# Generated by FakeRAM 2.0
VERSION 5.7 ;
BUSBITCHARS "[]" ;
PROPERTYDEFINITIONS
  MACRO width INTEGER ;
  MACRO depth INTEGER ;
  MACRO banks INTEGER ;
END PROPERTYDEFINITIONS
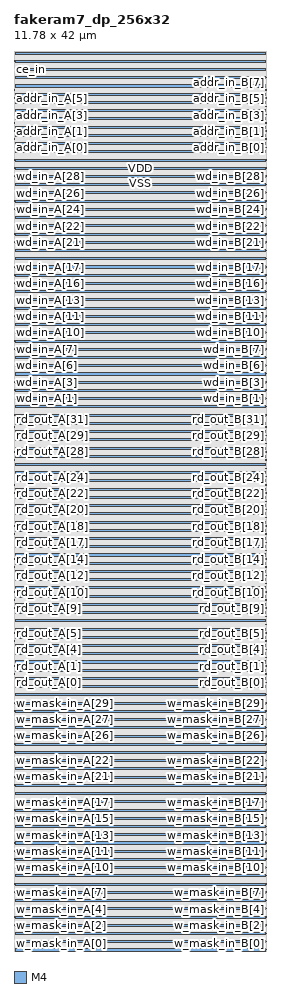
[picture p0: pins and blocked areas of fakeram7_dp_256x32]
MACRO fakeram7_dp_256x32
  PROPERTY width 32 ;
  PROPERTY depth 256 ;
  PROPERTY banks 2 ;
  FOREIGN fakeram7_dp_256x32 0 0 ;
  SYMMETRY X Y ;
  SIZE 11.780 BY 42.000 ;
  CLASS BLOCK ;
  PIN w_mask_in_A[0]
    DIRECTION INPUT ;
    USE SIGNAL ;
    SHAPE ABUTMENT ;
    PORT
      LAYER M4 ;
      RECT 0.000 0.048 0.024 0.072 ;
    END
  END w_mask_in_A[0]
  PIN w_mask_in_B[0]
    DIRECTION INPUT ;
    USE SIGNAL ;
    SHAPE ABUTMENT ;
    PORT
      LAYER M4 ;
      RECT 11.756 0.048 11.780 0.072 ;
    END
  END w_mask_in_B[0]
  PIN w_mask_in_A[1]
    DIRECTION INPUT ;
    USE SIGNAL ;
    SHAPE ABUTMENT ;
    PORT
      LAYER M4 ;
      RECT 0.000 0.432 0.024 0.456 ;
    END
  END w_mask_in_A[1]
  PIN w_mask_in_B[1]
    DIRECTION INPUT ;
    USE SIGNAL ;
    SHAPE ABUTMENT ;
    PORT
      LAYER M4 ;
      RECT 11.756 0.432 11.780 0.456 ;
    END
  END w_mask_in_B[1]
  PIN w_mask_in_A[2]
    DIRECTION INPUT ;
    USE SIGNAL ;
    SHAPE ABUTMENT ;
    PORT
      LAYER M4 ;
      RECT 0.000 0.816 0.024 0.840 ;
    END
  END w_mask_in_A[2]
  PIN w_mask_in_B[2]
    DIRECTION INPUT ;
    USE SIGNAL ;
    SHAPE ABUTMENT ;
    PORT
      LAYER M4 ;
      RECT 11.756 0.816 11.780 0.840 ;
    END
  END w_mask_in_B[2]
  PIN w_mask_in_A[3]
    DIRECTION INPUT ;
    USE SIGNAL ;
    SHAPE ABUTMENT ;
    PORT
      LAYER M4 ;
      RECT 0.000 1.200 0.024 1.224 ;
    END
  END w_mask_in_A[3]
  PIN w_mask_in_B[3]
    DIRECTION INPUT ;
    USE SIGNAL ;
    SHAPE ABUTMENT ;
    PORT
      LAYER M4 ;
      RECT 11.756 1.200 11.780 1.224 ;
    END
  END w_mask_in_B[3]
  PIN w_mask_in_A[4]
    DIRECTION INPUT ;
    USE SIGNAL ;
    SHAPE ABUTMENT ;
    PORT
      LAYER M4 ;
      RECT 0.000 1.584 0.024 1.608 ;
    END
  END w_mask_in_A[4]
  PIN w_mask_in_B[4]
    DIRECTION INPUT ;
    USE SIGNAL ;
    SHAPE ABUTMENT ;
    PORT
      LAYER M4 ;
      RECT 11.756 1.584 11.780 1.608 ;
    END
  END w_mask_in_B[4]
  PIN w_mask_in_A[5]
    DIRECTION INPUT ;
    USE SIGNAL ;
    SHAPE ABUTMENT ;
    PORT
      LAYER M4 ;
      RECT 0.000 1.968 0.024 1.992 ;
    END
  END w_mask_in_A[5]
  PIN w_mask_in_B[5]
    DIRECTION INPUT ;
    USE SIGNAL ;
    SHAPE ABUTMENT ;
    PORT
      LAYER M4 ;
      RECT 11.756 1.968 11.780 1.992 ;
    END
  END w_mask_in_B[5]
  PIN w_mask_in_A[6]
    DIRECTION INPUT ;
    USE SIGNAL ;
    SHAPE ABUTMENT ;
    PORT
      LAYER M4 ;
      RECT 0.000 2.352 0.024 2.376 ;
    END
  END w_mask_in_A[6]
  PIN w_mask_in_B[6]
    DIRECTION INPUT ;
    USE SIGNAL ;
    SHAPE ABUTMENT ;
    PORT
      LAYER M4 ;
      RECT 11.756 2.352 11.780 2.376 ;
    END
  END w_mask_in_B[6]
  PIN w_mask_in_A[7]
    DIRECTION INPUT ;
    USE SIGNAL ;
    SHAPE ABUTMENT ;
    PORT
      LAYER M4 ;
      RECT 0.000 2.736 0.024 2.760 ;
    END
  END w_mask_in_A[7]
  PIN w_mask_in_B[7]
    DIRECTION INPUT ;
    USE SIGNAL ;
    SHAPE ABUTMENT ;
    PORT
      LAYER M4 ;
      RECT 11.756 2.736 11.780 2.760 ;
    END
  END w_mask_in_B[7]
  PIN w_mask_in_A[8]
    DIRECTION INPUT ;
    USE SIGNAL ;
    SHAPE ABUTMENT ;
    PORT
      LAYER M4 ;
      RECT 0.000 3.120 0.024 3.144 ;
    END
  END w_mask_in_A[8]
  PIN w_mask_in_B[8]
    DIRECTION INPUT ;
    USE SIGNAL ;
    SHAPE ABUTMENT ;
    PORT
      LAYER M4 ;
      RECT 11.756 3.120 11.780 3.144 ;
    END
  END w_mask_in_B[8]
  PIN w_mask_in_A[9]
    DIRECTION INPUT ;
    USE SIGNAL ;
    SHAPE ABUTMENT ;
    PORT
      LAYER M4 ;
      RECT 0.000 3.504 0.024 3.528 ;
    END
  END w_mask_in_A[9]
  PIN w_mask_in_B[9]
    DIRECTION INPUT ;
    USE SIGNAL ;
    SHAPE ABUTMENT ;
    PORT
      LAYER M4 ;
      RECT 11.756 3.504 11.780 3.528 ;
    END
  END w_mask_in_B[9]
  PIN w_mask_in_A[10]
    DIRECTION INPUT ;
    USE SIGNAL ;
    SHAPE ABUTMENT ;
    PORT
      LAYER M4 ;
      RECT 0.000 3.888 0.024 3.912 ;
    END
  END w_mask_in_A[10]
  PIN w_mask_in_B[10]
    DIRECTION INPUT ;
    USE SIGNAL ;
    SHAPE ABUTMENT ;
    PORT
      LAYER M4 ;
      RECT 11.756 3.888 11.780 3.912 ;
    END
  END w_mask_in_B[10]
  PIN w_mask_in_A[11]
    DIRECTION INPUT ;
    USE SIGNAL ;
    SHAPE ABUTMENT ;
    PORT
      LAYER M4 ;
      RECT 0.000 4.272 0.024 4.296 ;
    END
  END w_mask_in_A[11]
  PIN w_mask_in_B[11]
    DIRECTION INPUT ;
    USE SIGNAL ;
    SHAPE ABUTMENT ;
    PORT
      LAYER M4 ;
      RECT 11.756 4.272 11.780 4.296 ;
    END
  END w_mask_in_B[11]
  PIN w_mask_in_A[12]
    DIRECTION INPUT ;
    USE SIGNAL ;
    SHAPE ABUTMENT ;
    PORT
      LAYER M4 ;
      RECT 0.000 4.656 0.024 4.680 ;
    END
  END w_mask_in_A[12]
  PIN w_mask_in_B[12]
    DIRECTION INPUT ;
    USE SIGNAL ;
    SHAPE ABUTMENT ;
    PORT
      LAYER M4 ;
      RECT 11.756 4.656 11.780 4.680 ;
    END
  END w_mask_in_B[12]
  PIN w_mask_in_A[13]
    DIRECTION INPUT ;
    USE SIGNAL ;
    SHAPE ABUTMENT ;
    PORT
      LAYER M4 ;
      RECT 0.000 5.040 0.024 5.064 ;
    END
  END w_mask_in_A[13]
  PIN w_mask_in_B[13]
    DIRECTION INPUT ;
    USE SIGNAL ;
    SHAPE ABUTMENT ;
    PORT
      LAYER M4 ;
      RECT 11.756 5.040 11.780 5.064 ;
    END
  END w_mask_in_B[13]
  PIN w_mask_in_A[14]
    DIRECTION INPUT ;
    USE SIGNAL ;
    SHAPE ABUTMENT ;
    PORT
      LAYER M4 ;
      RECT 0.000 5.424 0.024 5.448 ;
    END
  END w_mask_in_A[14]
  PIN w_mask_in_B[14]
    DIRECTION INPUT ;
    USE SIGNAL ;
    SHAPE ABUTMENT ;
    PORT
      LAYER M4 ;
      RECT 11.756 5.424 11.780 5.448 ;
    END
  END w_mask_in_B[14]
  PIN w_mask_in_A[15]
    DIRECTION INPUT ;
    USE SIGNAL ;
    SHAPE ABUTMENT ;
    PORT
      LAYER M4 ;
      RECT 0.000 5.808 0.024 5.832 ;
    END
  END w_mask_in_A[15]
  PIN w_mask_in_B[15]
    DIRECTION INPUT ;
    USE SIGNAL ;
    SHAPE ABUTMENT ;
    PORT
      LAYER M4 ;
      RECT 11.756 5.808 11.780 5.832 ;
    END
  END w_mask_in_B[15]
  PIN w_mask_in_A[16]
    DIRECTION INPUT ;
    USE SIGNAL ;
    SHAPE ABUTMENT ;
    PORT
      LAYER M4 ;
      RECT 0.000 6.192 0.024 6.216 ;
    END
  END w_mask_in_A[16]
  PIN w_mask_in_B[16]
    DIRECTION INPUT ;
    USE SIGNAL ;
    SHAPE ABUTMENT ;
    PORT
      LAYER M4 ;
      RECT 11.756 6.192 11.780 6.216 ;
    END
  END w_mask_in_B[16]
  PIN w_mask_in_A[17]
    DIRECTION INPUT ;
    USE SIGNAL ;
    SHAPE ABUTMENT ;
    PORT
      LAYER M4 ;
      RECT 0.000 6.576 0.024 6.600 ;
    END
  END w_mask_in_A[17]
  PIN w_mask_in_B[17]
    DIRECTION INPUT ;
    USE SIGNAL ;
    SHAPE ABUTMENT ;
    PORT
      LAYER M4 ;
      RECT 11.756 6.576 11.780 6.600 ;
    END
  END w_mask_in_B[17]
  PIN w_mask_in_A[18]
    DIRECTION INPUT ;
    USE SIGNAL ;
    SHAPE ABUTMENT ;
    PORT
      LAYER M4 ;
      RECT 0.000 6.960 0.024 6.984 ;
    END
  END w_mask_in_A[18]
  PIN w_mask_in_B[18]
    DIRECTION INPUT ;
    USE SIGNAL ;
    SHAPE ABUTMENT ;
    PORT
      LAYER M4 ;
      RECT 11.756 6.960 11.780 6.984 ;
    END
  END w_mask_in_B[18]
  PIN w_mask_in_A[19]
    DIRECTION INPUT ;
    USE SIGNAL ;
    SHAPE ABUTMENT ;
    PORT
      LAYER M4 ;
      RECT 0.000 7.344 0.024 7.368 ;
    END
  END w_mask_in_A[19]
  PIN w_mask_in_B[19]
    DIRECTION INPUT ;
    USE SIGNAL ;
    SHAPE ABUTMENT ;
    PORT
      LAYER M4 ;
      RECT 11.756 7.344 11.780 7.368 ;
    END
  END w_mask_in_B[19]
  PIN w_mask_in_A[20]
    DIRECTION INPUT ;
    USE SIGNAL ;
    SHAPE ABUTMENT ;
    PORT
      LAYER M4 ;
      RECT 0.000 7.728 0.024 7.752 ;
    END
  END w_mask_in_A[20]
  PIN w_mask_in_B[20]
    DIRECTION INPUT ;
    USE SIGNAL ;
    SHAPE ABUTMENT ;
    PORT
      LAYER M4 ;
      RECT 11.756 7.728 11.780 7.752 ;
    END
  END w_mask_in_B[20]
  PIN w_mask_in_A[21]
    DIRECTION INPUT ;
    USE SIGNAL ;
    SHAPE ABUTMENT ;
    PORT
      LAYER M4 ;
      RECT 0.000 8.112 0.024 8.136 ;
    END
  END w_mask_in_A[21]
  PIN w_mask_in_B[21]
    DIRECTION INPUT ;
    USE SIGNAL ;
    SHAPE ABUTMENT ;
    PORT
      LAYER M4 ;
      RECT 11.756 8.112 11.780 8.136 ;
    END
  END w_mask_in_B[21]
  PIN w_mask_in_A[22]
    DIRECTION INPUT ;
    USE SIGNAL ;
    SHAPE ABUTMENT ;
    PORT
      LAYER M4 ;
      RECT 0.000 8.496 0.024 8.520 ;
    END
  END w_mask_in_A[22]
  PIN w_mask_in_B[22]
    DIRECTION INPUT ;
    USE SIGNAL ;
    SHAPE ABUTMENT ;
    PORT
      LAYER M4 ;
      RECT 11.756 8.496 11.780 8.520 ;
    END
  END w_mask_in_B[22]
  PIN w_mask_in_A[23]
    DIRECTION INPUT ;
    USE SIGNAL ;
    SHAPE ABUTMENT ;
    PORT
      LAYER M4 ;
      RECT 0.000 8.880 0.024 8.904 ;
    END
  END w_mask_in_A[23]
  PIN w_mask_in_B[23]
    DIRECTION INPUT ;
    USE SIGNAL ;
    SHAPE ABUTMENT ;
    PORT
      LAYER M4 ;
      RECT 11.756 8.880 11.780 8.904 ;
    END
  END w_mask_in_B[23]
  PIN w_mask_in_A[24]
    DIRECTION INPUT ;
    USE SIGNAL ;
    SHAPE ABUTMENT ;
    PORT
      LAYER M4 ;
      RECT 0.000 9.264 0.024 9.288 ;
    END
  END w_mask_in_A[24]
  PIN w_mask_in_B[24]
    DIRECTION INPUT ;
    USE SIGNAL ;
    SHAPE ABUTMENT ;
    PORT
      LAYER M4 ;
      RECT 11.756 9.264 11.780 9.288 ;
    END
  END w_mask_in_B[24]
  PIN w_mask_in_A[25]
    DIRECTION INPUT ;
    USE SIGNAL ;
    SHAPE ABUTMENT ;
    PORT
      LAYER M4 ;
      RECT 0.000 9.648 0.024 9.672 ;
    END
  END w_mask_in_A[25]
  PIN w_mask_in_B[25]
    DIRECTION INPUT ;
    USE SIGNAL ;
    SHAPE ABUTMENT ;
    PORT
      LAYER M4 ;
      RECT 11.756 9.648 11.780 9.672 ;
    END
  END w_mask_in_B[25]
  PIN w_mask_in_A[26]
    DIRECTION INPUT ;
    USE SIGNAL ;
    SHAPE ABUTMENT ;
    PORT
      LAYER M4 ;
      RECT 0.000 10.032 0.024 10.056 ;
    END
  END w_mask_in_A[26]
  PIN w_mask_in_B[26]
    DIRECTION INPUT ;
    USE SIGNAL ;
    SHAPE ABUTMENT ;
    PORT
      LAYER M4 ;
      RECT 11.756 10.032 11.780 10.056 ;
    END
  END w_mask_in_B[26]
  PIN w_mask_in_A[27]
    DIRECTION INPUT ;
    USE SIGNAL ;
    SHAPE ABUTMENT ;
    PORT
      LAYER M4 ;
      RECT 0.000 10.416 0.024 10.440 ;
    END
  END w_mask_in_A[27]
  PIN w_mask_in_B[27]
    DIRECTION INPUT ;
    USE SIGNAL ;
    SHAPE ABUTMENT ;
    PORT
      LAYER M4 ;
      RECT 11.756 10.416 11.780 10.440 ;
    END
  END w_mask_in_B[27]
  PIN w_mask_in_A[28]
    DIRECTION INPUT ;
    USE SIGNAL ;
    SHAPE ABUTMENT ;
    PORT
      LAYER M4 ;
      RECT 0.000 10.800 0.024 10.824 ;
    END
  END w_mask_in_A[28]
  PIN w_mask_in_B[28]
    DIRECTION INPUT ;
    USE SIGNAL ;
    SHAPE ABUTMENT ;
    PORT
      LAYER M4 ;
      RECT 11.756 10.800 11.780 10.824 ;
    END
  END w_mask_in_B[28]
  PIN w_mask_in_A[29]
    DIRECTION INPUT ;
    USE SIGNAL ;
    SHAPE ABUTMENT ;
    PORT
      LAYER M4 ;
      RECT 0.000 11.184 0.024 11.208 ;
    END
  END w_mask_in_A[29]
  PIN w_mask_in_B[29]
    DIRECTION INPUT ;
    USE SIGNAL ;
    SHAPE ABUTMENT ;
    PORT
      LAYER M4 ;
      RECT 11.756 11.184 11.780 11.208 ;
    END
  END w_mask_in_B[29]
  PIN w_mask_in_A[30]
    DIRECTION INPUT ;
    USE SIGNAL ;
    SHAPE ABUTMENT ;
    PORT
      LAYER M4 ;
      RECT 0.000 11.568 0.024 11.592 ;
    END
  END w_mask_in_A[30]
  PIN w_mask_in_B[30]
    DIRECTION INPUT ;
    USE SIGNAL ;
    SHAPE ABUTMENT ;
    PORT
      LAYER M4 ;
      RECT 11.756 11.568 11.780 11.592 ;
    END
  END w_mask_in_B[30]
  PIN w_mask_in_A[31]
    DIRECTION INPUT ;
    USE SIGNAL ;
    SHAPE ABUTMENT ;
    PORT
      LAYER M4 ;
      RECT 0.000 11.952 0.024 11.976 ;
    END
  END w_mask_in_A[31]
  PIN w_mask_in_B[31]
    DIRECTION INPUT ;
    USE SIGNAL ;
    SHAPE ABUTMENT ;
    PORT
      LAYER M4 ;
      RECT 11.756 11.952 11.780 11.976 ;
    END
  END w_mask_in_B[31]
  PIN rd_out_A[0]
    DIRECTION OUTPUT ;
    USE SIGNAL ;
    SHAPE ABUTMENT ;
    PORT
      LAYER M4 ;
      RECT 0.000 12.528 0.024 12.552 ;
    END
  END rd_out_A[0]
  PIN rd_out_B[0]
    DIRECTION OUTPUT ;
    USE SIGNAL ;
    SHAPE ABUTMENT ;
    PORT
      LAYER M4 ;
      RECT 11.756 12.528 11.780 12.552 ;
    END
  END rd_out_B[0]
  PIN rd_out_A[1]
    DIRECTION OUTPUT ;
    USE SIGNAL ;
    SHAPE ABUTMENT ;
    PORT
      LAYER M4 ;
      RECT 0.000 12.912 0.024 12.936 ;
    END
  END rd_out_A[1]
  PIN rd_out_B[1]
    DIRECTION OUTPUT ;
    USE SIGNAL ;
    SHAPE ABUTMENT ;
    PORT
      LAYER M4 ;
      RECT 11.756 12.912 11.780 12.936 ;
    END
  END rd_out_B[1]
  PIN rd_out_A[2]
    DIRECTION OUTPUT ;
    USE SIGNAL ;
    SHAPE ABUTMENT ;
    PORT
      LAYER M4 ;
      RECT 0.000 13.296 0.024 13.320 ;
    END
  END rd_out_A[2]
  PIN rd_out_B[2]
    DIRECTION OUTPUT ;
    USE SIGNAL ;
    SHAPE ABUTMENT ;
    PORT
      LAYER M4 ;
      RECT 11.756 13.296 11.780 13.320 ;
    END
  END rd_out_B[2]
  PIN rd_out_A[3]
    DIRECTION OUTPUT ;
    USE SIGNAL ;
    SHAPE ABUTMENT ;
    PORT
      LAYER M4 ;
      RECT 0.000 13.680 0.024 13.704 ;
    END
  END rd_out_A[3]
  PIN rd_out_B[3]
    DIRECTION OUTPUT ;
    USE SIGNAL ;
    SHAPE ABUTMENT ;
    PORT
      LAYER M4 ;
      RECT 11.756 13.680 11.780 13.704 ;
    END
  END rd_out_B[3]
  PIN rd_out_A[4]
    DIRECTION OUTPUT ;
    USE SIGNAL ;
    SHAPE ABUTMENT ;
    PORT
      LAYER M4 ;
      RECT 0.000 14.064 0.024 14.088 ;
    END
  END rd_out_A[4]
  PIN rd_out_B[4]
    DIRECTION OUTPUT ;
    USE SIGNAL ;
    SHAPE ABUTMENT ;
    PORT
      LAYER M4 ;
      RECT 11.756 14.064 11.780 14.088 ;
    END
  END rd_out_B[4]
  PIN rd_out_A[5]
    DIRECTION OUTPUT ;
    USE SIGNAL ;
    SHAPE ABUTMENT ;
    PORT
      LAYER M4 ;
      RECT 0.000 14.448 0.024 14.472 ;
    END
  END rd_out_A[5]
  PIN rd_out_B[5]
    DIRECTION OUTPUT ;
    USE SIGNAL ;
    SHAPE ABUTMENT ;
    PORT
      LAYER M4 ;
      RECT 11.756 14.448 11.780 14.472 ;
    END
  END rd_out_B[5]
  PIN rd_out_A[6]
    DIRECTION OUTPUT ;
    USE SIGNAL ;
    SHAPE ABUTMENT ;
    PORT
      LAYER M4 ;
      RECT 0.000 14.832 0.024 14.856 ;
    END
  END rd_out_A[6]
  PIN rd_out_B[6]
    DIRECTION OUTPUT ;
    USE SIGNAL ;
    SHAPE ABUTMENT ;
    PORT
      LAYER M4 ;
      RECT 11.756 14.832 11.780 14.856 ;
    END
  END rd_out_B[6]
  PIN rd_out_A[7]
    DIRECTION OUTPUT ;
    USE SIGNAL ;
    SHAPE ABUTMENT ;
    PORT
      LAYER M4 ;
      RECT 0.000 15.216 0.024 15.240 ;
    END
  END rd_out_A[7]
  PIN rd_out_B[7]
    DIRECTION OUTPUT ;
    USE SIGNAL ;
    SHAPE ABUTMENT ;
    PORT
      LAYER M4 ;
      RECT 11.756 15.216 11.780 15.240 ;
    END
  END rd_out_B[7]
  PIN rd_out_A[8]
    DIRECTION OUTPUT ;
    USE SIGNAL ;
    SHAPE ABUTMENT ;
    PORT
      LAYER M4 ;
      RECT 0.000 15.600 0.024 15.624 ;
    END
  END rd_out_A[8]
  PIN rd_out_B[8]
    DIRECTION OUTPUT ;
    USE SIGNAL ;
    SHAPE ABUTMENT ;
    PORT
      LAYER M4 ;
      RECT 11.756 15.600 11.780 15.624 ;
    END
  END rd_out_B[8]
  PIN rd_out_A[9]
    DIRECTION OUTPUT ;
    USE SIGNAL ;
    SHAPE ABUTMENT ;
    PORT
      LAYER M4 ;
      RECT 0.000 15.984 0.024 16.008 ;
    END
  END rd_out_A[9]
  PIN rd_out_B[9]
    DIRECTION OUTPUT ;
    USE SIGNAL ;
    SHAPE ABUTMENT ;
    PORT
      LAYER M4 ;
      RECT 11.756 15.984 11.780 16.008 ;
    END
  END rd_out_B[9]
  PIN rd_out_A[10]
    DIRECTION OUTPUT ;
    USE SIGNAL ;
    SHAPE ABUTMENT ;
    PORT
      LAYER M4 ;
      RECT 0.000 16.368 0.024 16.392 ;
    END
  END rd_out_A[10]
  PIN rd_out_B[10]
    DIRECTION OUTPUT ;
    USE SIGNAL ;
    SHAPE ABUTMENT ;
    PORT
      LAYER M4 ;
      RECT 11.756 16.368 11.780 16.392 ;
    END
  END rd_out_B[10]
  PIN rd_out_A[11]
    DIRECTION OUTPUT ;
    USE SIGNAL ;
    SHAPE ABUTMENT ;
    PORT
      LAYER M4 ;
      RECT 0.000 16.752 0.024 16.776 ;
    END
  END rd_out_A[11]
  PIN rd_out_B[11]
    DIRECTION OUTPUT ;
    USE SIGNAL ;
    SHAPE ABUTMENT ;
    PORT
      LAYER M4 ;
      RECT 11.756 16.752 11.780 16.776 ;
    END
  END rd_out_B[11]
  PIN rd_out_A[12]
    DIRECTION OUTPUT ;
    USE SIGNAL ;
    SHAPE ABUTMENT ;
    PORT
      LAYER M4 ;
      RECT 0.000 17.136 0.024 17.160 ;
    END
  END rd_out_A[12]
  PIN rd_out_B[12]
    DIRECTION OUTPUT ;
    USE SIGNAL ;
    SHAPE ABUTMENT ;
    PORT
      LAYER M4 ;
      RECT 11.756 17.136 11.780 17.160 ;
    END
  END rd_out_B[12]
  PIN rd_out_A[13]
    DIRECTION OUTPUT ;
    USE SIGNAL ;
    SHAPE ABUTMENT ;
    PORT
      LAYER M4 ;
      RECT 0.000 17.520 0.024 17.544 ;
    END
  END rd_out_A[13]
  PIN rd_out_B[13]
    DIRECTION OUTPUT ;
    USE SIGNAL ;
    SHAPE ABUTMENT ;
    PORT
      LAYER M4 ;
      RECT 11.756 17.520 11.780 17.544 ;
    END
  END rd_out_B[13]
  PIN rd_out_A[14]
    DIRECTION OUTPUT ;
    USE SIGNAL ;
    SHAPE ABUTMENT ;
    PORT
      LAYER M4 ;
      RECT 0.000 17.904 0.024 17.928 ;
    END
  END rd_out_A[14]
  PIN rd_out_B[14]
    DIRECTION OUTPUT ;
    USE SIGNAL ;
    SHAPE ABUTMENT ;
    PORT
      LAYER M4 ;
      RECT 11.756 17.904 11.780 17.928 ;
    END
  END rd_out_B[14]
  PIN rd_out_A[15]
    DIRECTION OUTPUT ;
    USE SIGNAL ;
    SHAPE ABUTMENT ;
    PORT
      LAYER M4 ;
      RECT 0.000 18.288 0.024 18.312 ;
    END
  END rd_out_A[15]
  PIN rd_out_B[15]
    DIRECTION OUTPUT ;
    USE SIGNAL ;
    SHAPE ABUTMENT ;
    PORT
      LAYER M4 ;
      RECT 11.756 18.288 11.780 18.312 ;
    END
  END rd_out_B[15]
  PIN rd_out_A[16]
    DIRECTION OUTPUT ;
    USE SIGNAL ;
    SHAPE ABUTMENT ;
    PORT
      LAYER M4 ;
      RECT 0.000 18.672 0.024 18.696 ;
    END
  END rd_out_A[16]
  PIN rd_out_B[16]
    DIRECTION OUTPUT ;
    USE SIGNAL ;
    SHAPE ABUTMENT ;
    PORT
      LAYER M4 ;
      RECT 11.756 18.672 11.780 18.696 ;
    END
  END rd_out_B[16]
  PIN rd_out_A[17]
    DIRECTION OUTPUT ;
    USE SIGNAL ;
    SHAPE ABUTMENT ;
    PORT
      LAYER M4 ;
      RECT 0.000 19.056 0.024 19.080 ;
    END
  END rd_out_A[17]
  PIN rd_out_B[17]
    DIRECTION OUTPUT ;
    USE SIGNAL ;
    SHAPE ABUTMENT ;
    PORT
      LAYER M4 ;
      RECT 11.756 19.056 11.780 19.080 ;
    END
  END rd_out_B[17]
  PIN rd_out_A[18]
    DIRECTION OUTPUT ;
    USE SIGNAL ;
    SHAPE ABUTMENT ;
    PORT
      LAYER M4 ;
      RECT 0.000 19.440 0.024 19.464 ;
    END
  END rd_out_A[18]
  PIN rd_out_B[18]
    DIRECTION OUTPUT ;
    USE SIGNAL ;
    SHAPE ABUTMENT ;
    PORT
      LAYER M4 ;
      RECT 11.756 19.440 11.780 19.464 ;
    END
  END rd_out_B[18]
  PIN rd_out_A[19]
    DIRECTION OUTPUT ;
    USE SIGNAL ;
    SHAPE ABUTMENT ;
    PORT
      LAYER M4 ;
      RECT 0.000 19.824 0.024 19.848 ;
    END
  END rd_out_A[19]
  PIN rd_out_B[19]
    DIRECTION OUTPUT ;
    USE SIGNAL ;
    SHAPE ABUTMENT ;
    PORT
      LAYER M4 ;
      RECT 11.756 19.824 11.780 19.848 ;
    END
  END rd_out_B[19]
  PIN rd_out_A[20]
    DIRECTION OUTPUT ;
    USE SIGNAL ;
    SHAPE ABUTMENT ;
    PORT
      LAYER M4 ;
      RECT 0.000 20.208 0.024 20.232 ;
    END
  END rd_out_A[20]
  PIN rd_out_B[20]
    DIRECTION OUTPUT ;
    USE SIGNAL ;
    SHAPE ABUTMENT ;
    PORT
      LAYER M4 ;
      RECT 11.756 20.208 11.780 20.232 ;
    END
  END rd_out_B[20]
  PIN rd_out_A[21]
    DIRECTION OUTPUT ;
    USE SIGNAL ;
    SHAPE ABUTMENT ;
    PORT
      LAYER M4 ;
      RECT 0.000 20.592 0.024 20.616 ;
    END
  END rd_out_A[21]
  PIN rd_out_B[21]
    DIRECTION OUTPUT ;
    USE SIGNAL ;
    SHAPE ABUTMENT ;
    PORT
      LAYER M4 ;
      RECT 11.756 20.592 11.780 20.616 ;
    END
  END rd_out_B[21]
  PIN rd_out_A[22]
    DIRECTION OUTPUT ;
    USE SIGNAL ;
    SHAPE ABUTMENT ;
    PORT
      LAYER M4 ;
      RECT 0.000 20.976 0.024 21.000 ;
    END
  END rd_out_A[22]
  PIN rd_out_B[22]
    DIRECTION OUTPUT ;
    USE SIGNAL ;
    SHAPE ABUTMENT ;
    PORT
      LAYER M4 ;
      RECT 11.756 20.976 11.780 21.000 ;
    END
  END rd_out_B[22]
  PIN rd_out_A[23]
    DIRECTION OUTPUT ;
    USE SIGNAL ;
    SHAPE ABUTMENT ;
    PORT
      LAYER M4 ;
      RECT 0.000 21.360 0.024 21.384 ;
    END
  END rd_out_A[23]
  PIN rd_out_B[23]
    DIRECTION OUTPUT ;
    USE SIGNAL ;
    SHAPE ABUTMENT ;
    PORT
      LAYER M4 ;
      RECT 11.756 21.360 11.780 21.384 ;
    END
  END rd_out_B[23]
  PIN rd_out_A[24]
    DIRECTION OUTPUT ;
    USE SIGNAL ;
    SHAPE ABUTMENT ;
    PORT
      LAYER M4 ;
      RECT 0.000 21.744 0.024 21.768 ;
    END
  END rd_out_A[24]
  PIN rd_out_B[24]
    DIRECTION OUTPUT ;
    USE SIGNAL ;
    SHAPE ABUTMENT ;
    PORT
      LAYER M4 ;
      RECT 11.756 21.744 11.780 21.768 ;
    END
  END rd_out_B[24]
  PIN rd_out_A[25]
    DIRECTION OUTPUT ;
    USE SIGNAL ;
    SHAPE ABUTMENT ;
    PORT
      LAYER M4 ;
      RECT 0.000 22.128 0.024 22.152 ;
    END
  END rd_out_A[25]
  PIN rd_out_B[25]
    DIRECTION OUTPUT ;
    USE SIGNAL ;
    SHAPE ABUTMENT ;
    PORT
      LAYER M4 ;
      RECT 11.756 22.128 11.780 22.152 ;
    END
  END rd_out_B[25]
  PIN rd_out_A[26]
    DIRECTION OUTPUT ;
    USE SIGNAL ;
    SHAPE ABUTMENT ;
    PORT
      LAYER M4 ;
      RECT 0.000 22.512 0.024 22.536 ;
    END
  END rd_out_A[26]
  PIN rd_out_B[26]
    DIRECTION OUTPUT ;
    USE SIGNAL ;
    SHAPE ABUTMENT ;
    PORT
      LAYER M4 ;
      RECT 11.756 22.512 11.780 22.536 ;
    END
  END rd_out_B[26]
  PIN rd_out_A[27]
    DIRECTION OUTPUT ;
    USE SIGNAL ;
    SHAPE ABUTMENT ;
    PORT
      LAYER M4 ;
      RECT 0.000 22.896 0.024 22.920 ;
    END
  END rd_out_A[27]
  PIN rd_out_B[27]
    DIRECTION OUTPUT ;
    USE SIGNAL ;
    SHAPE ABUTMENT ;
    PORT
      LAYER M4 ;
      RECT 11.756 22.896 11.780 22.920 ;
    END
  END rd_out_B[27]
  PIN rd_out_A[28]
    DIRECTION OUTPUT ;
    USE SIGNAL ;
    SHAPE ABUTMENT ;
    PORT
      LAYER M4 ;
      RECT 0.000 23.280 0.024 23.304 ;
    END
  END rd_out_A[28]
  PIN rd_out_B[28]
    DIRECTION OUTPUT ;
    USE SIGNAL ;
    SHAPE ABUTMENT ;
    PORT
      LAYER M4 ;
      RECT 11.756 23.280 11.780 23.304 ;
    END
  END rd_out_B[28]
  PIN rd_out_A[29]
    DIRECTION OUTPUT ;
    USE SIGNAL ;
    SHAPE ABUTMENT ;
    PORT
      LAYER M4 ;
      RECT 0.000 23.664 0.024 23.688 ;
    END
  END rd_out_A[29]
  PIN rd_out_B[29]
    DIRECTION OUTPUT ;
    USE SIGNAL ;
    SHAPE ABUTMENT ;
    PORT
      LAYER M4 ;
      RECT 11.756 23.664 11.780 23.688 ;
    END
  END rd_out_B[29]
  PIN rd_out_A[30]
    DIRECTION OUTPUT ;
    USE SIGNAL ;
    SHAPE ABUTMENT ;
    PORT
      LAYER M4 ;
      RECT 0.000 24.048 0.024 24.072 ;
    END
  END rd_out_A[30]
  PIN rd_out_B[30]
    DIRECTION OUTPUT ;
    USE SIGNAL ;
    SHAPE ABUTMENT ;
    PORT
      LAYER M4 ;
      RECT 11.756 24.048 11.780 24.072 ;
    END
  END rd_out_B[30]
  PIN rd_out_A[31]
    DIRECTION OUTPUT ;
    USE SIGNAL ;
    SHAPE ABUTMENT ;
    PORT
      LAYER M4 ;
      RECT 0.000 24.432 0.024 24.456 ;
    END
  END rd_out_A[31]
  PIN rd_out_B[31]
    DIRECTION OUTPUT ;
    USE SIGNAL ;
    SHAPE ABUTMENT ;
    PORT
      LAYER M4 ;
      RECT 11.756 24.432 11.780 24.456 ;
    END
  END rd_out_B[31]
  PIN wd_in_A[0]
    DIRECTION INPUT ;
    USE SIGNAL ;
    SHAPE ABUTMENT ;
    PORT
      LAYER M4 ;
      RECT 0.000 25.008 0.024 25.032 ;
    END
  END wd_in_A[0]
  PIN wd_in_B[0]
    DIRECTION INPUT ;
    USE SIGNAL ;
    SHAPE ABUTMENT ;
    PORT
      LAYER M4 ;
      RECT 11.756 25.008 11.780 25.032 ;
    END
  END wd_in_B[0]
  PIN wd_in_A[1]
    DIRECTION INPUT ;
    USE SIGNAL ;
    SHAPE ABUTMENT ;
    PORT
      LAYER M4 ;
      RECT 0.000 25.392 0.024 25.416 ;
    END
  END wd_in_A[1]
  PIN wd_in_B[1]
    DIRECTION INPUT ;
    USE SIGNAL ;
    SHAPE ABUTMENT ;
    PORT
      LAYER M4 ;
      RECT 11.756 25.392 11.780 25.416 ;
    END
  END wd_in_B[1]
  PIN wd_in_A[2]
    DIRECTION INPUT ;
    USE SIGNAL ;
    SHAPE ABUTMENT ;
    PORT
      LAYER M4 ;
      RECT 0.000 25.776 0.024 25.800 ;
    END
  END wd_in_A[2]
  PIN wd_in_B[2]
    DIRECTION INPUT ;
    USE SIGNAL ;
    SHAPE ABUTMENT ;
    PORT
      LAYER M4 ;
      RECT 11.756 25.776 11.780 25.800 ;
    END
  END wd_in_B[2]
  PIN wd_in_A[3]
    DIRECTION INPUT ;
    USE SIGNAL ;
    SHAPE ABUTMENT ;
    PORT
      LAYER M4 ;
      RECT 0.000 26.160 0.024 26.184 ;
    END
  END wd_in_A[3]
  PIN wd_in_B[3]
    DIRECTION INPUT ;
    USE SIGNAL ;
    SHAPE ABUTMENT ;
    PORT
      LAYER M4 ;
      RECT 11.756 26.160 11.780 26.184 ;
    END
  END wd_in_B[3]
  PIN wd_in_A[4]
    DIRECTION INPUT ;
    USE SIGNAL ;
    SHAPE ABUTMENT ;
    PORT
      LAYER M4 ;
      RECT 0.000 26.544 0.024 26.568 ;
    END
  END wd_in_A[4]
  PIN wd_in_B[4]
    DIRECTION INPUT ;
    USE SIGNAL ;
    SHAPE ABUTMENT ;
    PORT
      LAYER M4 ;
      RECT 11.756 26.544 11.780 26.568 ;
    END
  END wd_in_B[4]
  PIN wd_in_A[5]
    DIRECTION INPUT ;
    USE SIGNAL ;
    SHAPE ABUTMENT ;
    PORT
      LAYER M4 ;
      RECT 0.000 26.928 0.024 26.952 ;
    END
  END wd_in_A[5]
  PIN wd_in_B[5]
    DIRECTION INPUT ;
    USE SIGNAL ;
    SHAPE ABUTMENT ;
    PORT
      LAYER M4 ;
      RECT 11.756 26.928 11.780 26.952 ;
    END
  END wd_in_B[5]
  PIN wd_in_A[6]
    DIRECTION INPUT ;
    USE SIGNAL ;
    SHAPE ABUTMENT ;
    PORT
      LAYER M4 ;
      RECT 0.000 27.312 0.024 27.336 ;
    END
  END wd_in_A[6]
  PIN wd_in_B[6]
    DIRECTION INPUT ;
    USE SIGNAL ;
    SHAPE ABUTMENT ;
    PORT
      LAYER M4 ;
      RECT 11.756 27.312 11.780 27.336 ;
    END
  END wd_in_B[6]
  PIN wd_in_A[7]
    DIRECTION INPUT ;
    USE SIGNAL ;
    SHAPE ABUTMENT ;
    PORT
      LAYER M4 ;
      RECT 0.000 27.696 0.024 27.720 ;
    END
  END wd_in_A[7]
  PIN wd_in_B[7]
    DIRECTION INPUT ;
    USE SIGNAL ;
    SHAPE ABUTMENT ;
    PORT
      LAYER M4 ;
      RECT 11.756 27.696 11.780 27.720 ;
    END
  END wd_in_B[7]
  PIN wd_in_A[8]
    DIRECTION INPUT ;
    USE SIGNAL ;
    SHAPE ABUTMENT ;
    PORT
      LAYER M4 ;
      RECT 0.000 28.080 0.024 28.104 ;
    END
  END wd_in_A[8]
  PIN wd_in_B[8]
    DIRECTION INPUT ;
    USE SIGNAL ;
    SHAPE ABUTMENT ;
    PORT
      LAYER M4 ;
      RECT 11.756 28.080 11.780 28.104 ;
    END
  END wd_in_B[8]
  PIN wd_in_A[9]
    DIRECTION INPUT ;
    USE SIGNAL ;
    SHAPE ABUTMENT ;
    PORT
      LAYER M4 ;
      RECT 0.000 28.464 0.024 28.488 ;
    END
  END wd_in_A[9]
  PIN wd_in_B[9]
    DIRECTION INPUT ;
    USE SIGNAL ;
    SHAPE ABUTMENT ;
    PORT
      LAYER M4 ;
      RECT 11.756 28.464 11.780 28.488 ;
    END
  END wd_in_B[9]
  PIN wd_in_A[10]
    DIRECTION INPUT ;
    USE SIGNAL ;
    SHAPE ABUTMENT ;
    PORT
      LAYER M4 ;
      RECT 0.000 28.848 0.024 28.872 ;
    END
  END wd_in_A[10]
  PIN wd_in_B[10]
    DIRECTION INPUT ;
    USE SIGNAL ;
    SHAPE ABUTMENT ;
    PORT
      LAYER M4 ;
      RECT 11.756 28.848 11.780 28.872 ;
    END
  END wd_in_B[10]
  PIN wd_in_A[11]
    DIRECTION INPUT ;
    USE SIGNAL ;
    SHAPE ABUTMENT ;
    PORT
      LAYER M4 ;
      RECT 0.000 29.232 0.024 29.256 ;
    END
  END wd_in_A[11]
  PIN wd_in_B[11]
    DIRECTION INPUT ;
    USE SIGNAL ;
    SHAPE ABUTMENT ;
    PORT
      LAYER M4 ;
      RECT 11.756 29.232 11.780 29.256 ;
    END
  END wd_in_B[11]
  PIN wd_in_A[12]
    DIRECTION INPUT ;
    USE SIGNAL ;
    SHAPE ABUTMENT ;
    PORT
      LAYER M4 ;
      RECT 0.000 29.616 0.024 29.640 ;
    END
  END wd_in_A[12]
  PIN wd_in_B[12]
    DIRECTION INPUT ;
    USE SIGNAL ;
    SHAPE ABUTMENT ;
    PORT
      LAYER M4 ;
      RECT 11.756 29.616 11.780 29.640 ;
    END
  END wd_in_B[12]
  PIN wd_in_A[13]
    DIRECTION INPUT ;
    USE SIGNAL ;
    SHAPE ABUTMENT ;
    PORT
      LAYER M4 ;
      RECT 0.000 30.000 0.024 30.024 ;
    END
  END wd_in_A[13]
  PIN wd_in_B[13]
    DIRECTION INPUT ;
    USE SIGNAL ;
    SHAPE ABUTMENT ;
    PORT
      LAYER M4 ;
      RECT 11.756 30.000 11.780 30.024 ;
    END
  END wd_in_B[13]
  PIN wd_in_A[14]
    DIRECTION INPUT ;
    USE SIGNAL ;
    SHAPE ABUTMENT ;
    PORT
      LAYER M4 ;
      RECT 0.000 30.384 0.024 30.408 ;
    END
  END wd_in_A[14]
  PIN wd_in_B[14]
    DIRECTION INPUT ;
    USE SIGNAL ;
    SHAPE ABUTMENT ;
    PORT
      LAYER M4 ;
      RECT 11.756 30.384 11.780 30.408 ;
    END
  END wd_in_B[14]
  PIN wd_in_A[15]
    DIRECTION INPUT ;
    USE SIGNAL ;
    SHAPE ABUTMENT ;
    PORT
      LAYER M4 ;
      RECT 0.000 30.768 0.024 30.792 ;
    END
  END wd_in_A[15]
  PIN wd_in_B[15]
    DIRECTION INPUT ;
    USE SIGNAL ;
    SHAPE ABUTMENT ;
    PORT
      LAYER M4 ;
      RECT 11.756 30.768 11.780 30.792 ;
    END
  END wd_in_B[15]
  PIN wd_in_A[16]
    DIRECTION INPUT ;
    USE SIGNAL ;
    SHAPE ABUTMENT ;
    PORT
      LAYER M4 ;
      RECT 0.000 31.152 0.024 31.176 ;
    END
  END wd_in_A[16]
  PIN wd_in_B[16]
    DIRECTION INPUT ;
    USE SIGNAL ;
    SHAPE ABUTMENT ;
    PORT
      LAYER M4 ;
      RECT 11.756 31.152 11.780 31.176 ;
    END
  END wd_in_B[16]
  PIN wd_in_A[17]
    DIRECTION INPUT ;
    USE SIGNAL ;
    SHAPE ABUTMENT ;
    PORT
      LAYER M4 ;
      RECT 0.000 31.536 0.024 31.560 ;
    END
  END wd_in_A[17]
  PIN wd_in_B[17]
    DIRECTION INPUT ;
    USE SIGNAL ;
    SHAPE ABUTMENT ;
    PORT
      LAYER M4 ;
      RECT 11.756 31.536 11.780 31.560 ;
    END
  END wd_in_B[17]
  PIN wd_in_A[18]
    DIRECTION INPUT ;
    USE SIGNAL ;
    SHAPE ABUTMENT ;
    PORT
      LAYER M4 ;
      RECT 0.000 31.920 0.024 31.944 ;
    END
  END wd_in_A[18]
  PIN wd_in_B[18]
    DIRECTION INPUT ;
    USE SIGNAL ;
    SHAPE ABUTMENT ;
    PORT
      LAYER M4 ;
      RECT 11.756 31.920 11.780 31.944 ;
    END
  END wd_in_B[18]
  PIN wd_in_A[19]
    DIRECTION INPUT ;
    USE SIGNAL ;
    SHAPE ABUTMENT ;
    PORT
      LAYER M4 ;
      RECT 0.000 32.304 0.024 32.328 ;
    END
  END wd_in_A[19]
  PIN wd_in_B[19]
    DIRECTION INPUT ;
    USE SIGNAL ;
    SHAPE ABUTMENT ;
    PORT
      LAYER M4 ;
      RECT 11.756 32.304 11.780 32.328 ;
    END
  END wd_in_B[19]
  PIN wd_in_A[20]
    DIRECTION INPUT ;
    USE SIGNAL ;
    SHAPE ABUTMENT ;
    PORT
      LAYER M4 ;
      RECT 0.000 32.688 0.024 32.712 ;
    END
  END wd_in_A[20]
  PIN wd_in_B[20]
    DIRECTION INPUT ;
    USE SIGNAL ;
    SHAPE ABUTMENT ;
    PORT
      LAYER M4 ;
      RECT 11.756 32.688 11.780 32.712 ;
    END
  END wd_in_B[20]
  PIN wd_in_A[21]
    DIRECTION INPUT ;
    USE SIGNAL ;
    SHAPE ABUTMENT ;
    PORT
      LAYER M4 ;
      RECT 0.000 33.072 0.024 33.096 ;
    END
  END wd_in_A[21]
  PIN wd_in_B[21]
    DIRECTION INPUT ;
    USE SIGNAL ;
    SHAPE ABUTMENT ;
    PORT
      LAYER M4 ;
      RECT 11.756 33.072 11.780 33.096 ;
    END
  END wd_in_B[21]
  PIN wd_in_A[22]
    DIRECTION INPUT ;
    USE SIGNAL ;
    SHAPE ABUTMENT ;
    PORT
      LAYER M4 ;
      RECT 0.000 33.456 0.024 33.480 ;
    END
  END wd_in_A[22]
  PIN wd_in_B[22]
    DIRECTION INPUT ;
    USE SIGNAL ;
    SHAPE ABUTMENT ;
    PORT
      LAYER M4 ;
      RECT 11.756 33.456 11.780 33.480 ;
    END
  END wd_in_B[22]
  PIN wd_in_A[23]
    DIRECTION INPUT ;
    USE SIGNAL ;
    SHAPE ABUTMENT ;
    PORT
      LAYER M4 ;
      RECT 0.000 33.840 0.024 33.864 ;
    END
  END wd_in_A[23]
  PIN wd_in_B[23]
    DIRECTION INPUT ;
    USE SIGNAL ;
    SHAPE ABUTMENT ;
    PORT
      LAYER M4 ;
      RECT 11.756 33.840 11.780 33.864 ;
    END
  END wd_in_B[23]
  PIN wd_in_A[24]
    DIRECTION INPUT ;
    USE SIGNAL ;
    SHAPE ABUTMENT ;
    PORT
      LAYER M4 ;
      RECT 0.000 34.224 0.024 34.248 ;
    END
  END wd_in_A[24]
  PIN wd_in_B[24]
    DIRECTION INPUT ;
    USE SIGNAL ;
    SHAPE ABUTMENT ;
    PORT
      LAYER M4 ;
      RECT 11.756 34.224 11.780 34.248 ;
    END
  END wd_in_B[24]
  PIN wd_in_A[25]
    DIRECTION INPUT ;
    USE SIGNAL ;
    SHAPE ABUTMENT ;
    PORT
      LAYER M4 ;
      RECT 0.000 34.608 0.024 34.632 ;
    END
  END wd_in_A[25]
  PIN wd_in_B[25]
    DIRECTION INPUT ;
    USE SIGNAL ;
    SHAPE ABUTMENT ;
    PORT
      LAYER M4 ;
      RECT 11.756 34.608 11.780 34.632 ;
    END
  END wd_in_B[25]
  PIN wd_in_A[26]
    DIRECTION INPUT ;
    USE SIGNAL ;
    SHAPE ABUTMENT ;
    PORT
      LAYER M4 ;
      RECT 0.000 34.992 0.024 35.016 ;
    END
  END wd_in_A[26]
  PIN wd_in_B[26]
    DIRECTION INPUT ;
    USE SIGNAL ;
    SHAPE ABUTMENT ;
    PORT
      LAYER M4 ;
      RECT 11.756 34.992 11.780 35.016 ;
    END
  END wd_in_B[26]
  PIN wd_in_A[27]
    DIRECTION INPUT ;
    USE SIGNAL ;
    SHAPE ABUTMENT ;
    PORT
      LAYER M4 ;
      RECT 0.000 35.376 0.024 35.400 ;
    END
  END wd_in_A[27]
  PIN wd_in_B[27]
    DIRECTION INPUT ;
    USE SIGNAL ;
    SHAPE ABUTMENT ;
    PORT
      LAYER M4 ;
      RECT 11.756 35.376 11.780 35.400 ;
    END
  END wd_in_B[27]
  PIN wd_in_A[28]
    DIRECTION INPUT ;
    USE SIGNAL ;
    SHAPE ABUTMENT ;
    PORT
      LAYER M4 ;
      RECT 0.000 35.760 0.024 35.784 ;
    END
  END wd_in_A[28]
  PIN wd_in_B[28]
    DIRECTION INPUT ;
    USE SIGNAL ;
    SHAPE ABUTMENT ;
    PORT
      LAYER M4 ;
      RECT 11.756 35.760 11.780 35.784 ;
    END
  END wd_in_B[28]
  PIN wd_in_A[29]
    DIRECTION INPUT ;
    USE SIGNAL ;
    SHAPE ABUTMENT ;
    PORT
      LAYER M4 ;
      RECT 0.000 36.144 0.024 36.168 ;
    END
  END wd_in_A[29]
  PIN wd_in_B[29]
    DIRECTION INPUT ;
    USE SIGNAL ;
    SHAPE ABUTMENT ;
    PORT
      LAYER M4 ;
      RECT 11.756 36.144 11.780 36.168 ;
    END
  END wd_in_B[29]
  PIN wd_in_A[30]
    DIRECTION INPUT ;
    USE SIGNAL ;
    SHAPE ABUTMENT ;
    PORT
      LAYER M4 ;
      RECT 0.000 36.528 0.024 36.552 ;
    END
  END wd_in_A[30]
  PIN wd_in_B[30]
    DIRECTION INPUT ;
    USE SIGNAL ;
    SHAPE ABUTMENT ;
    PORT
      LAYER M4 ;
      RECT 11.756 36.528 11.780 36.552 ;
    END
  END wd_in_B[30]
  PIN wd_in_A[31]
    DIRECTION INPUT ;
    USE SIGNAL ;
    SHAPE ABUTMENT ;
    PORT
      LAYER M4 ;
      RECT 0.000 36.912 0.024 36.936 ;
    END
  END wd_in_A[31]
  PIN wd_in_B[31]
    DIRECTION INPUT ;
    USE SIGNAL ;
    SHAPE ABUTMENT ;
    PORT
      LAYER M4 ;
      RECT 11.756 36.912 11.780 36.936 ;
    END
  END wd_in_B[31]
  PIN addr_in_A[0]
    DIRECTION INPUT ;
    USE SIGNAL ;
    SHAPE ABUTMENT ;
    PORT
      LAYER M4 ;
      RECT 0.000 37.488 0.024 37.512 ;
    END
  END addr_in_A[0]
  PIN addr_in_B[0]
    DIRECTION INPUT ;
    USE SIGNAL ;
    SHAPE ABUTMENT ;
    PORT
      LAYER M4 ;
      RECT 11.756 37.488 11.780 37.512 ;
    END
  END addr_in_B[0]
  PIN addr_in_A[1]
    DIRECTION INPUT ;
    USE SIGNAL ;
    SHAPE ABUTMENT ;
    PORT
      LAYER M4 ;
      RECT 0.000 37.872 0.024 37.896 ;
    END
  END addr_in_A[1]
  PIN addr_in_B[1]
    DIRECTION INPUT ;
    USE SIGNAL ;
    SHAPE ABUTMENT ;
    PORT
      LAYER M4 ;
      RECT 11.756 37.872 11.780 37.896 ;
    END
  END addr_in_B[1]
  PIN addr_in_A[2]
    DIRECTION INPUT ;
    USE SIGNAL ;
    SHAPE ABUTMENT ;
    PORT
      LAYER M4 ;
      RECT 0.000 38.256 0.024 38.280 ;
    END
  END addr_in_A[2]
  PIN addr_in_B[2]
    DIRECTION INPUT ;
    USE SIGNAL ;
    SHAPE ABUTMENT ;
    PORT
      LAYER M4 ;
      RECT 11.756 38.256 11.780 38.280 ;
    END
  END addr_in_B[2]
  PIN addr_in_A[3]
    DIRECTION INPUT ;
    USE SIGNAL ;
    SHAPE ABUTMENT ;
    PORT
      LAYER M4 ;
      RECT 0.000 38.640 0.024 38.664 ;
    END
  END addr_in_A[3]
  PIN addr_in_B[3]
    DIRECTION INPUT ;
    USE SIGNAL ;
    SHAPE ABUTMENT ;
    PORT
      LAYER M4 ;
      RECT 11.756 38.640 11.780 38.664 ;
    END
  END addr_in_B[3]
  PIN addr_in_A[4]
    DIRECTION INPUT ;
    USE SIGNAL ;
    SHAPE ABUTMENT ;
    PORT
      LAYER M4 ;
      RECT 0.000 39.024 0.024 39.048 ;
    END
  END addr_in_A[4]
  PIN addr_in_B[4]
    DIRECTION INPUT ;
    USE SIGNAL ;
    SHAPE ABUTMENT ;
    PORT
      LAYER M4 ;
      RECT 11.756 39.024 11.780 39.048 ;
    END
  END addr_in_B[4]
  PIN addr_in_A[5]
    DIRECTION INPUT ;
    USE SIGNAL ;
    SHAPE ABUTMENT ;
    PORT
      LAYER M4 ;
      RECT 0.000 39.408 0.024 39.432 ;
    END
  END addr_in_A[5]
  PIN addr_in_B[5]
    DIRECTION INPUT ;
    USE SIGNAL ;
    SHAPE ABUTMENT ;
    PORT
      LAYER M4 ;
      RECT 11.756 39.408 11.780 39.432 ;
    END
  END addr_in_B[5]
  PIN addr_in_A[6]
    DIRECTION INPUT ;
    USE SIGNAL ;
    SHAPE ABUTMENT ;
    PORT
      LAYER M4 ;
      RECT 0.000 39.792 0.024 39.816 ;
    END
  END addr_in_A[6]
  PIN addr_in_B[6]
    DIRECTION INPUT ;
    USE SIGNAL ;
    SHAPE ABUTMENT ;
    PORT
      LAYER M4 ;
      RECT 11.756 39.792 11.780 39.816 ;
    END
  END addr_in_B[6]
  PIN addr_in_A[7]
    DIRECTION INPUT ;
    USE SIGNAL ;
    SHAPE ABUTMENT ;
    PORT
      LAYER M4 ;
      RECT 0.000 40.176 0.024 40.200 ;
    END
  END addr_in_A[7]
  PIN addr_in_B[7]
    DIRECTION INPUT ;
    USE SIGNAL ;
    SHAPE ABUTMENT ;
    PORT
      LAYER M4 ;
      RECT 11.756 40.176 11.780 40.200 ;
    END
  END addr_in_B[7]
  PIN we_in_A
    DIRECTION INPUT ;
    USE SIGNAL ;
    SHAPE ABUTMENT ;
    PORT
      LAYER M4 ;
      RECT 0.000 40.752 0.024 40.776 ;
    END
  END we_in_A
  PIN we_in_B
    DIRECTION INPUT ;
    USE SIGNAL ;
    SHAPE ABUTMENT ;
    PORT
      LAYER M4 ;
      RECT 11.756 40.752 11.780 40.776 ;
    END
  END we_in_B
  PIN ce_in
    DIRECTION INPUT ;
    USE SIGNAL ;
    SHAPE ABUTMENT ;
    PORT
      LAYER M4 ;
      RECT 0.000 41.136 0.024 41.160 ;
    END
  END ce_in
  PIN clk
    DIRECTION INPUT ;
    USE SIGNAL ;
    SHAPE ABUTMENT ;
    PORT
      LAYER M4 ;
      RECT 0.000 41.520 0.024 41.544 ;
    END
  END clk
  PIN VSS
    DIRECTION INOUT ;
    USE GROUND ;
    PORT
      LAYER M4 ;
      RECT 0.048 0.000 11.732 0.096 ;
      RECT 0.048 0.768 11.732 0.864 ;
      RECT 0.048 1.536 11.732 1.632 ;
      RECT 0.048 2.304 11.732 2.400 ;
      RECT 0.048 3.072 11.732 3.168 ;
      RECT 0.048 3.840 11.732 3.936 ;
      RECT 0.048 4.608 11.732 4.704 ;
      RECT 0.048 5.376 11.732 5.472 ;
      RECT 0.048 6.144 11.732 6.240 ;
      RECT 0.048 6.912 11.732 7.008 ;
      RECT 0.048 7.680 11.732 7.776 ;
      RECT 0.048 8.448 11.732 8.544 ;
      RECT 0.048 9.216 11.732 9.312 ;
      RECT 0.048 9.984 11.732 10.080 ;
      RECT 0.048 10.752 11.732 10.848 ;
      RECT 0.048 11.520 11.732 11.616 ;
      RECT 0.048 12.288 11.732 12.384 ;
      RECT 0.048 13.056 11.732 13.152 ;
      RECT 0.048 13.824 11.732 13.920 ;
      RECT 0.048 14.592 11.732 14.688 ;
      RECT 0.048 15.360 11.732 15.456 ;
      RECT 0.048 16.128 11.732 16.224 ;
      RECT 0.048 16.896 11.732 16.992 ;
      RECT 0.048 17.664 11.732 17.760 ;
      RECT 0.048 18.432 11.732 18.528 ;
      RECT 0.048 19.200 11.732 19.296 ;
      RECT 0.048 19.968 11.732 20.064 ;
      RECT 0.048 20.736 11.732 20.832 ;
      RECT 0.048 21.504 11.732 21.600 ;
      RECT 0.048 22.272 11.732 22.368 ;
      RECT 0.048 23.040 11.732 23.136 ;
      RECT 0.048 23.808 11.732 23.904 ;
      RECT 0.048 24.576 11.732 24.672 ;
      RECT 0.048 25.344 11.732 25.440 ;
      RECT 0.048 26.112 11.732 26.208 ;
      RECT 0.048 26.880 11.732 26.976 ;
      RECT 0.048 27.648 11.732 27.744 ;
      RECT 0.048 28.416 11.732 28.512 ;
      RECT 0.048 29.184 11.732 29.280 ;
      RECT 0.048 29.952 11.732 30.048 ;
      RECT 0.048 30.720 11.732 30.816 ;
      RECT 0.048 31.488 11.732 31.584 ;
      RECT 0.048 32.256 11.732 32.352 ;
      RECT 0.048 33.024 11.732 33.120 ;
      RECT 0.048 33.792 11.732 33.888 ;
      RECT 0.048 34.560 11.732 34.656 ;
      RECT 0.048 35.328 11.732 35.424 ;
      RECT 0.048 36.096 11.732 36.192 ;
      RECT 0.048 36.864 11.732 36.960 ;
      RECT 0.048 37.632 11.732 37.728 ;
      RECT 0.048 38.400 11.732 38.496 ;
      RECT 0.048 39.168 11.732 39.264 ;
      RECT 0.048 39.936 11.732 40.032 ;
      RECT 0.048 40.704 11.732 40.800 ;
      RECT 0.048 41.472 11.732 41.568 ;
    END
  END VSS
  PIN VDD
    DIRECTION INOUT ;
    USE POWER ;
    PORT
      LAYER M4 ;
      RECT 0.048 0.384 11.732 0.480 ;
      RECT 0.048 1.152 11.732 1.248 ;
      RECT 0.048 1.920 11.732 2.016 ;
      RECT 0.048 2.688 11.732 2.784 ;
      RECT 0.048 3.456 11.732 3.552 ;
      RECT 0.048 4.224 11.732 4.320 ;
      RECT 0.048 4.992 11.732 5.088 ;
      RECT 0.048 5.760 11.732 5.856 ;
      RECT 0.048 6.528 11.732 6.624 ;
      RECT 0.048 7.296 11.732 7.392 ;
      RECT 0.048 8.064 11.732 8.160 ;
      RECT 0.048 8.832 11.732 8.928 ;
      RECT 0.048 9.600 11.732 9.696 ;
      RECT 0.048 10.368 11.732 10.464 ;
      RECT 0.048 11.136 11.732 11.232 ;
      RECT 0.048 11.904 11.732 12.000 ;
      RECT 0.048 12.672 11.732 12.768 ;
      RECT 0.048 13.440 11.732 13.536 ;
      RECT 0.048 14.208 11.732 14.304 ;
      RECT 0.048 14.976 11.732 15.072 ;
      RECT 0.048 15.744 11.732 15.840 ;
      RECT 0.048 16.512 11.732 16.608 ;
      RECT 0.048 17.280 11.732 17.376 ;
      RECT 0.048 18.048 11.732 18.144 ;
      RECT 0.048 18.816 11.732 18.912 ;
      RECT 0.048 19.584 11.732 19.680 ;
      RECT 0.048 20.352 11.732 20.448 ;
      RECT 0.048 21.120 11.732 21.216 ;
      RECT 0.048 21.888 11.732 21.984 ;
      RECT 0.048 22.656 11.732 22.752 ;
      RECT 0.048 23.424 11.732 23.520 ;
      RECT 0.048 24.192 11.732 24.288 ;
      RECT 0.048 24.960 11.732 25.056 ;
      RECT 0.048 25.728 11.732 25.824 ;
      RECT 0.048 26.496 11.732 26.592 ;
      RECT 0.048 27.264 11.732 27.360 ;
      RECT 0.048 28.032 11.732 28.128 ;
      RECT 0.048 28.800 11.732 28.896 ;
      RECT 0.048 29.568 11.732 29.664 ;
      RECT 0.048 30.336 11.732 30.432 ;
      RECT 0.048 31.104 11.732 31.200 ;
      RECT 0.048 31.872 11.732 31.968 ;
      RECT 0.048 32.640 11.732 32.736 ;
      RECT 0.048 33.408 11.732 33.504 ;
      RECT 0.048 34.176 11.732 34.272 ;
      RECT 0.048 34.944 11.732 35.040 ;
      RECT 0.048 35.712 11.732 35.808 ;
      RECT 0.048 36.480 11.732 36.576 ;
      RECT 0.048 37.248 11.732 37.344 ;
      RECT 0.048 38.016 11.732 38.112 ;
      RECT 0.048 38.784 11.732 38.880 ;
      RECT 0.048 39.552 11.732 39.648 ;
      RECT 0.048 40.320 11.732 40.416 ;
      RECT 0.048 41.088 11.732 41.184 ;
      RECT 0.048 41.856 11.732 41.952 ;
    END
  END VDD
  OBS
    LAYER M1 ;
    RECT 0 0 11.780 42.000 ;
    LAYER M2 ;
    RECT 0 0 11.780 42.000 ;
    LAYER M3 ;
    RECT 0 0 11.780 42.000 ;
    LAYER M4 ;
    RECT 0 0 11.780 42.000 ;
  END
END fakeram7_dp_256x32

END LIBRARY
